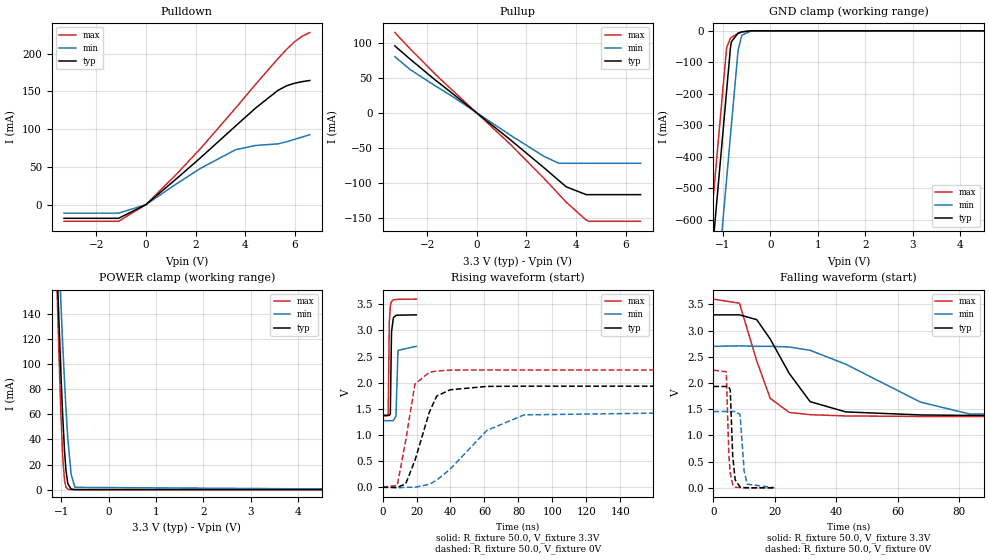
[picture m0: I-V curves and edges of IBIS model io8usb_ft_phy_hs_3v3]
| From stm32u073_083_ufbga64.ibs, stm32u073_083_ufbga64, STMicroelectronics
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[Model]   io8usb_ft_phy_hs_3v3
Model_type I/O
Polarity   Inverting
Enable   Active-Low
| CAP_THRESHOLD on pad DNFT is "UDTCAPC" :
| Rising=30.0% of vddiom   Falling=70.0% of vddiom
| C_comp min and max val. don't necessarily correlate with the min and max pvt
| but are the smallest and greatest pad capacitance found.
| var   typ   min   max
C_comp   7.92736pF  7.79845pF  11.45835pF
|C_comp_pullup   4.07400pF  4.14685pF  7.78900pF
|C_comp_pulldown   3.85336pF  3.65160pF  3.66935pF
Vinl = 810.0mV
Vinh = 2.52V
Vmeas = 1.65V   | Reference voltage for timing measurements
Cref  = 0F   | Timing specification test load capacitance value
Rref  = 100.0MOhm   | Timing specification test load resistance value
Vref  = 1.65V   | Timing specification test load voltage
[Model Spec]
| TIME_THRESHOLD on pin ZINV12 is "CMOS" :
| Rising=50.0% of vdd   Falling=50.0% of vdd
Vinl 1.34770V 1.11470V 1.44970V
Vinh 1.77530V 1.49030V 1.90330V
| variable   typ   min   max
[Temperature Range] 25.0 140.0 -40.0
| variable   typ   min   max
[Voltage Range] 3.3V 2.7V 3.6V
| variable   typ   min   max
[POWER Clamp Reference] 3.3V 2.7V 3.6V
| variable   typ   min   max
[GND Clamp Reference] 0V 0V 0V
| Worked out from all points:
|   slope of the pulldown table from 0 to 0.495 V, typ, clamps not added: 35.9 ohm
|   slope of the pullup table from 0 to 0.495 V, typ, clamps not added: 35.4 ohm
|   GND clamp passes 1 mA (typ) near -0.52 V on its own axis
|   POWER clamp passes 1 mA (typ) near -0.81 V on its own axis
|   rising waveform, R_fixture 50.0, V_fixture 3.3V: 20-80 % time 461ps typ, 449ps min, 469ps max; typ from 1.38 V to 3.3 V
|   falling waveform, R_fixture 50.0, V_fixture 3.3V: 20-80 % time 12ns typ, 32.2ns min, 7.05ns max; typ from 3.3 V to 1.38 V
|   rising waveform, R_fixture 50.0, V_fixture 0V: 20-80 % time 11ns typ, 27ns min, 6.46ns max; typ from 0 V to 1.93 V
|   falling waveform, R_fixture 50.0, V_fixture 0V: 20-80 % time 787ps typ, 1ns min, 711ps max; typ from 1.93 V to 0.001 V
[POWER Clamp]
-3.3V     2.991A     2.546A     3.694A
-1.11V    202.2mA    242.3mA    190.9mA
-1.09V    180mA      223.6mA    163.4mA
-1.05V    136.9mA    187mA      110.9mA
-1.01V    96.55mA    151.6mA    64.02mA
-970mV    60.39mA    117.9mA    27.41mA
-930mV    31.08mA    86.54mA    7.282mA
-900mV    15.67mA    65.13mA    2.025mA
-860mV    4.779mA    40.5mA     315.2uA
-790mV    394.2uA    12.22mA    11.25uA
-710mV    19.95uA    1.811mA    247.1nA
6.6V      0A         0A         0A
[GND Clamp]
-3.3V     -4.235A    -4.516A    -4.096A
-1.39V    -988.3mA   -1.268A    -848.9mA
-1.24V    -733.3mA   -1.014A    -593.9mA
-1.23V    -716.3mA   -996.5mA   -576.9mA
-1.1V     -495.3mA   -775.5mA   -355.9mA
-920mV    -189.3mA   -469.5mA   -53.02mA
-840mV    -54.5mA    -333.5mA   -23.28mA
-820mV    -35.01mA   -299.5mA   -20.98mA
-680mV    -7.53mA    -63.11mA   -8.471mA
-600mV    -3.376mA   -13.82mA   -3.494mA
-400mV    -43.64uA   -366.2uA   -14.84uA
6.6V      2.843nA    1.369uA    2.06nA
| variable   typ   min   max
[Pullup Reference] 3.3V 2.7V 3.6V
| variable   typ   min   max
[Pulldown Reference] 0V 0V 0V
[Pullup]
-3.3V     96.3mA     80.9mA     115.4mA
-2.69V    77.5mA     62.6mA     92.4mA
-1.66V    47.03mA    38.72mA    55.3mA
-1.08V    30.92mA    26.11mA    35.95mA
1.37V     -38.8mA    -32.07mA   -45.39mA
2.7V      -78.18mA   -61.93mA   -93.34mA
3.3V      -96.52mA   -71.93mA   -116.2mA
3.6V      -105.7mA   -71.93mA   -127.7mA
4.41V     -117mA     -71.93mA   -153.5mA
4.53V     -117mA     -71.93mA   -155.2mA
6.6V      -117mA     -71.93mA   -155.2mA
[Pulldown]
-3.3V     -18.14mA   -11.3mA    -22.1mA
-1.1V     -18.14mA   -11.3mA    -22.1mA
0V        432.9pA    53.29nA    569.7pA
1.27V     35.39mA    28.4mA     41.65mA
2.21V     62.41mA    48.22mA    74.69mA
3.6V      103.8mA    72.59mA    127.4mA
4.41V     127.7mA    78.32mA    159.1mA
5.32V     151.4mA    80.5mA     193.5mA
5.68V     157.6mA    83.4mA     206.1mA
5.99V     160.8mA    86.5mA     215.8mA
6.31V     163mA      89.7mA     223.4mA
6.6V      164.4mA    92.6mA     227.9mA
[Ramp]
dV/dt_r 1.16051V/10.86112ns 874.33602mV/25.9067ns 1.34678V/6.45665ns
dV/dt_f 1.15341V/11.93378ns 855.09845mV/29.64984ns 1.34305V/7.04833ns
R_load = 50.0
| Removed startup time: 0s 0s 0s  .
| Removed end time: 19.9ns.
[Rising Waveform]
R_fixture   = 50.0
V_fixture   = 3.3V
V_fixture_min = 2.7V
V_fixture_max = 3.6V
0s        1.378V     1.275V     1.362V
3.3ns     1.378V     1.275V     1.368V
4ns       1.377V     1.275V     3.17V
4.6ns     1.407V     1.275V     3.47V
4.9ns     2.144V     1.275V     3.519V
5.3ns     2.976V     1.275V     3.554V
6.4ns     3.244V     1.275V     3.586V
7.9ns     3.289V     1.36V      3.593V
9.1ns     3.293V     2.619V     3.596V
19.9ns    3.299V     2.698V     3.6V
| Removed startup time: 0s 0s 0s  .
| Removed end time: 249.9ns.
[Falling Waveform]
R_fixture   = 50.0
V_fixture   = 3.3V
V_fixture_min = 2.7V
V_fixture_max = 3.6V
0s        3.3V       2.7V       3.6V
8.5ns     3.3V       2.709V     3.522V
14.1ns    3.209V     2.7V       2.424V
18.5ns    2.839V     2.7V       1.709V
24.7ns    2.182V     2.687V     1.438V
31.5ns    1.644V     2.624V     1.396V
43.1ns    1.449V     2.358V     1.372V
67.4ns    1.391V     1.636V     1.362V
83.3ns    1.382V     1.41V      1.362V
249.9ns   1.378V     1.275V     1.362V
| Removed startup time: 0s 0s 0s  .
| Removed end time: 249.9ns.
[Rising Waveform]
R_fixture   = 50.0
V_fixture   = 0V
V_fixture_min = 0V
V_fixture_max = 0V
0s        78.83nV    580.1nV    47.37nV
8.7ns     -1.609mV   -11.39mV   35.72mV
13.6ns    63.48mV    -660.1uV   887.9mV
19.1ns    514.5mV    404.2uV    1.977V
27.6ns    1.442V     57.27mV    2.201V
31.9ns    1.745V     136.8mV    2.225V
39.8ns    1.865V     347.2mV    2.241V
61.4ns    1.93V      1.087V     2.245V
83.3ns    1.934V     1.385V     2.245V
249.9ns   1.934V     1.457V     2.245V
| Removed startup time: 0s 0s 0s  .
| Removed end time: 19.9ns.
[Falling Waveform]
R_fixture   = 50.0
V_fixture   = 0V
V_fixture_min = 0V
V_fixture_max = 0V
0s        1.934V     1.457V     2.245V
4.2ns     1.934V     1.457V     2.216V
5ns       1.935V     1.457V     667.7mV
5.5ns     1.861V     1.457V     269.8mV
6.3ns     604.6mV    1.457V     58.45mV
7.1ns     152.5mV    1.457V     13.79mV
8.7ns     15.05mV    1.397V     3.764mV
10ns      4.646mV    336.1mV    2.73mV
11ns      2.669mV    69.75mV    2.346mV
19.9ns    908.6uV    4.096mV    169.6uV
